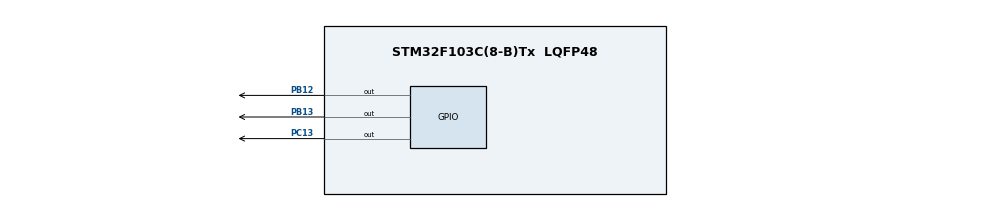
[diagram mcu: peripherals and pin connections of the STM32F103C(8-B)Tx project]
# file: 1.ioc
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Mcu.Family=STM32F1
Mcu.Name=STM32F103C(8-B)Tx
Mcu.Package=LQFP48
NVIC.PriorityGroup=NVIC_PRIORITYGROUP_4
PA13.Mode=Serial_Wire
PA13.Signal=SYS_JTMS-SWDIO
PA14.Mode=Serial_Wire
PA14.Signal=SYS_JTCK-SWCLK
PB12.GPIO_ModeDefaultOutputPP=GPIO_MODE_OUTPUT_OD
PB12.GPIO_PuPd=GPIO_PULLUP
PB12.GPIO_Speed=GPIO_SPEED_FREQ_HIGH
PB12.Signal=GPIO_Output
PB13.GPIO_ModeDefaultOutputPP=GPIO_MODE_OUTPUT_OD
PB13.GPIO_PuPd=GPIO_PULLUP
PB13.GPIO_Speed=GPIO_SPEED_FREQ_HIGH
PB13.Signal=GPIO_Output
PC13-TAMPER-RTC.PinState=GPIO_PIN_SET
PC13-TAMPER-RTC.Signal=GPIO_Output
PD0-OSC_IN.Mode=HSE-External-Oscillator
PD0-OSC_IN.Signal=RCC_OSC_IN
PD1-OSC_OUT.Mode=HSE-External-Oscillator
PD1-OSC_OUT.Signal=RCC_OSC_OUT
ProjectManager.HeapSize=0x200
ProjectManager.StackSize=0x400
ProjectManager.TargetToolchain=MDK-ARM V5.32
RCC.AHBFreq_Value=72000000
RCC.APB1CLKDivider=RCC_HCLK_DIV2
RCC.APB1Freq_Value=36000000
RCC.APB1TimFreq_Value=72000000
RCC.APB2Freq_Value=72000000
RCC.APB2TimFreq_Value=72000000
RCC.HCLKFreq_Value=72000000
RCC.PLLMUL=RCC_PLL_MUL9
RCC.PLLSourceVirtual=RCC_PLLSOURCE_HSE
RCC.SYSCLKFreq_VALUE=72000000
RCC.SYSCLKSource=RCC_SYSCLKSOURCE_PLLCLK
RCC.USBFreq_Value=72000000
board=custom

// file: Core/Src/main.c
/* USER CODE BEGIN Header */
/**
  ******************************************************************************
  * @file           : main.c
  * @brief          : Main program body
  ******************************************************************************
  * @attention
  *
  * Copyright (c) 2024 STMicroelectronics.
  * All rights reserved.
  *
  * This software is licensed under terms that can be found in the LICENSE file
  * in the root directory of this software component.
  * If no LICENSE file comes with this software, it is provided AS-IS.
  *
  ******************************************************************************
  */
/* USER CODE END Header */
#include "main.h"
#include "gpio.h"

/* USER CODE BEGIN Includes */
#include "MPU6050.h"
#include "kem.h"
/* USER CODE END Includes */

/* USER CODE BEGIN PV */
void Delay_us(uint32_t xus)
{
	SysTick->LOAD = 72 * xus;
	SysTick->VAL = 0x00;
	SysTick->CTRL = 0x00000005;
	while (!(SysTick->CTRL & (1 << 16)))
		;
	SysTick->CTRL = 0x00000004;
}
void Delay_ms(uint32_t xms)
{
	uint32_t i = xms;
	while (i--)
	{
		Delay_us(1000);
	}
}
int16_t Roll_angle;
int16_t Pitch_angle;
/* USER CODE END PV */

void SystemClock_Config(void);

/* USER CODE BEGIN 0 */
SixAxisData data;
Angle angle;
extern uint8_t Test;
/* USER CODE END 0 */

int main(void)
{
  HAL_Init();
  SystemClock_Config();
  MX_GPIO_Init();

  while (1)
  {

  }
  /* USER CODE END 3 */
}

void SystemClock_Config(void)
{
  RCC_OscInitTypeDef RCC_OscInitStruct = {0};
  RCC_ClkInitTypeDef RCC_ClkInitStruct = {0};

  /** Initializes the RCC Oscillators according to the specified parameters
  * in the RCC_OscInitTypeDef structure.
  */
  RCC_OscInitStruct.OscillatorType = RCC_OSCILLATORTYPE_HSE;
  RCC_OscInitStruct.HSEState = RCC_HSE_ON;
  RCC_OscInitStruct.HSEPredivValue = RCC_HSE_PREDIV_DIV2;
  RCC_OscInitStruct.HSIState = RCC_HSI_ON;
  RCC_OscInitStruct.PLL.PLLState = RCC_PLL_ON;
  RCC_OscInitStruct.PLL.PLLSource = RCC_PLLSOURCE_HSE;
  RCC_OscInitStruct.PLL.PLLMUL = RCC_PLL_MUL15;
  if (HAL_RCC_OscConfig(&RCC_OscInitStruct) != HAL_OK)
  {
    Error_Handler();
  }

  /** Initializes the CPU, AHB and APB buses clocks
  */
  RCC_ClkInitStruct.ClockType = RCC_CLOCKTYPE_HCLK|RCC_CLOCKTYPE_SYSCLK
                              |RCC_CLOCKTYPE_PCLK1|RCC_CLOCKTYPE_PCLK2;
  RCC_ClkInitStruct.SYSCLKSource = RCC_SYSCLKSOURCE_PLLCLK;
  RCC_ClkInitStruct.AHBCLKDivider = RCC_SYSCLK_DIV1;
  RCC_ClkInitStruct.APB1CLKDivider = RCC_HCLK_DIV2;
  RCC_ClkInitStruct.APB2CLKDivider = RCC_HCLK_DIV1;

  if (HAL_RCC_ClockConfig(&RCC_ClkInitStruct, FLASH_LATENCY_2) != HAL_OK)
  {
    Error_Handler();
  }
}

void Error_Handler(void)
{
  __disable_irq();
  while (1)
  {
  }
}
